VERSION 5.8 ;
BUSBITCHARS "[]" ;
DIVIDERCHAR "/" ;

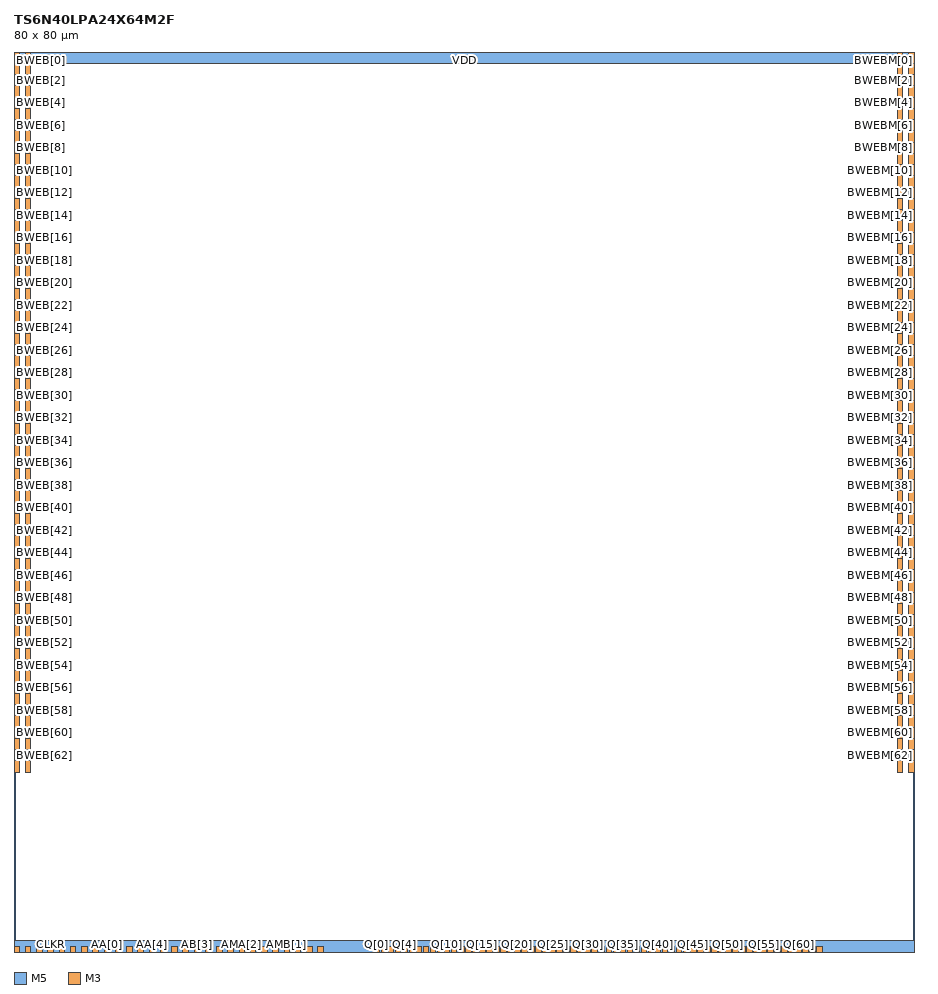
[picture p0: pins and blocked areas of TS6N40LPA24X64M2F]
MACRO TS6N40LPA24X64M2F
  CLASS BLOCK ;
  ORIGIN 0 0 ;
  SIZE 80.0 BY 80.0 ;
  SITE core ;
  SYMMETRY X Y ;

  # ===== Power / Ground =====
  PIN VDD
    DIRECTION INOUT ; USE POWER ;
    PORT
      LAYER M5 ;
        RECT 0.0 79.0 80.0 80.0 ;
    END
  END VDD

  PIN VSS
    DIRECTION INOUT ; USE GROUND ;
    PORT
      LAYER M5 ;
        RECT 0.0 0.0 80.0 1.0 ;
    END
  END VSS

  # ===== Scalars on SOUTH edge (x = 0..32 band) =====
  # order: WEB, CLKW, REB, CLKR, PD, WEBM, REBM, BIST  (step 1.0, width 0.5)
  PIN WEB   DIRECTION INPUT ; USE SIGNAL ;  PORT LAYER M3 ; RECT  0.00 0.00  0.50 0.50 ; END  END WEB
  PIN CLKW  DIRECTION INPUT ; USE SIGNAL ;  PORT LAYER M3 ; RECT  1.00 0.00  1.50 0.50 ; END  END CLKW
  PIN REB   DIRECTION INPUT ; USE SIGNAL ;  PORT LAYER M3 ; RECT  2.00 0.00  2.50 0.50 ; END  END REB
  PIN CLKR  DIRECTION INPUT ; USE SIGNAL ;  PORT LAYER M3 ; RECT  3.00 0.00  3.50 0.50 ; END  END CLKR
  PIN PD    DIRECTION INPUT ; USE SIGNAL ;  PORT LAYER M3 ; RECT  4.00 0.00  4.50 0.50 ; END  END PD
  PIN WEBM  DIRECTION INPUT ; USE SIGNAL ;  PORT LAYER M3 ; RECT  5.00 0.00  5.50 0.50 ; END  END WEBM
  PIN REBM  DIRECTION INPUT ; USE SIGNAL ;  PORT LAYER M3 ; RECT  6.00 0.00  6.50 0.50 ; END  END REBM
  PIN BIST  DIRECTION INPUT ; USE SIGNAL ;  PORT LAYER M3 ; RECT  7.00 0.00  7.50 0.50 ; END  END BIST

  # ===== Address buses (SOUTH, still in x = 0..32 band), step 1.0, width 0.5 =====
  # AA[4:0]
  PIN AA[0] DIRECTION INPUT ; USE SIGNAL ;  PORT LAYER M3 ; RECT  8.00 0.00  8.50 0.50 ; END  END AA[0]
  PIN AA[1] DIRECTION INPUT ; USE SIGNAL ;  PORT LAYER M3 ; RECT  9.00 0.00  9.50 0.50 ; END  END AA[1]
  PIN AA[2] DIRECTION INPUT ; USE SIGNAL ;  PORT LAYER M3 ; RECT 10.00 0.00 10.50 0.50 ; END  END AA[2]
  PIN AA[3] DIRECTION INPUT ; USE SIGNAL ;  PORT LAYER M3 ; RECT 11.00 0.00 11.50 0.50 ; END  END AA[3]
  PIN AA[4] DIRECTION INPUT ; USE SIGNAL ;  PORT LAYER M3 ; RECT 12.00 0.00 12.50 0.50 ; END  END AA[4]

  # AB[4:0]
  PIN AB[0] DIRECTION INPUT ; USE SIGNAL ;  PORT LAYER M3 ; RECT 13.00 0.00 13.50 0.50 ; END  END AB[0]
  PIN AB[1] DIRECTION INPUT ; USE SIGNAL ;  PORT LAYER M3 ; RECT 14.00 0.00 14.50 0.50 ; END  END AB[1]
  PIN AB[2] DIRECTION INPUT ; USE SIGNAL ;  PORT LAYER M3 ; RECT 15.00 0.00 15.50 0.50 ; END  END AB[2]
  PIN AB[3] DIRECTION INPUT ; USE SIGNAL ;  PORT LAYER M3 ; RECT 16.00 0.00 16.50 0.50 ; END  END AB[3]
  PIN AB[4] DIRECTION INPUT ; USE SIGNAL ;  PORT LAYER M3 ; RECT 17.00 0.00 17.50 0.50 ; END  END AB[4]

  # AMA[4:0]
  PIN AMA[0] DIRECTION INPUT ; USE SIGNAL ; PORT LAYER M3 ; RECT 18.00 0.00 18.50 0.50 ; END  END AMA[0]
  PIN AMA[1] DIRECTION INPUT ; USE SIGNAL ; PORT LAYER M3 ; RECT 19.00 0.00 19.50 0.50 ; END  END AMA[1]
  PIN AMA[2] DIRECTION INPUT ; USE SIGNAL ; PORT LAYER M3 ; RECT 20.00 0.00 20.50 0.50 ; END  END AMA[2]
  PIN AMA[3] DIRECTION INPUT ; USE SIGNAL ; PORT LAYER M3 ; RECT 21.00 0.00 21.50 0.50 ; END  END AMA[3]
  PIN AMA[4] DIRECTION INPUT ; USE SIGNAL ; PORT LAYER M3 ; RECT 22.00 0.00 22.50 0.50 ; END  END AMA[4]

  # AMB[4:0]
  PIN AMB[0] DIRECTION INPUT ; USE SIGNAL ; PORT LAYER M3 ; RECT 23.00 0.00 23.50 0.50 ; END  END AMB[0]
  PIN AMB[1] DIRECTION INPUT ; USE SIGNAL ; PORT LAYER M3 ; RECT 24.00 0.00 24.50 0.50 ; END  END AMB[1]
  PIN AMB[2] DIRECTION INPUT ; USE SIGNAL ; PORT LAYER M3 ; RECT 25.00 0.00 25.50 0.50 ; END  END AMB[2]
  PIN AMB[3] DIRECTION INPUT ; USE SIGNAL ; PORT LAYER M3 ; RECT 26.00 0.00 26.50 0.50 ; END  END AMB[3]
  PIN AMB[4] DIRECTION INPUT ; USE SIGNAL ; PORT LAYER M3 ; RECT 27.00 0.00 27.50 0.50 ; END  END AMB[4]

  # (leave x=27..32 empty as a spacer before Q bus)

  # ===== Q[63:0] on SOUTH edge (x = 32..80), step 0.625, width 0.5 =====
  # y = 0.0–0.5
  PIN Q[0]  DIRECTION OUTPUT ; USE SIGNAL ;  PORT LAYER M3 ; RECT 32.000 0.00 32.500 0.50 ; END  END Q[0]
  PIN Q[1]  DIRECTION OUTPUT ; USE SIGNAL ;  PORT LAYER M3 ; RECT 32.625 0.00 33.125 0.50 ; END  END Q[1]
  PIN Q[2]  DIRECTION OUTPUT ; USE SIGNAL ;  PORT LAYER M3 ; RECT 33.250 0.00 33.750 0.50 ; END  END Q[2]
  PIN Q[3]  DIRECTION OUTPUT ; USE SIGNAL ;  PORT LAYER M3 ; RECT 33.875 0.00 34.375 0.50 ; END  END Q[3]
  PIN Q[4]  DIRECTION OUTPUT ; USE SIGNAL ;  PORT LAYER M3 ; RECT 34.500 0.00 35.000 0.50 ; END  END Q[4]
  PIN Q[5]  DIRECTION OUTPUT ; USE SIGNAL ;  PORT LAYER M3 ; RECT 35.125 0.00 35.625 0.50 ; END  END Q[5]
  PIN Q[6]  DIRECTION OUTPUT ; USE SIGNAL ;  PORT LAYER M3 ; RECT 35.750 0.00 36.250 0.50 ; END  END Q[6]
  PIN Q[7]  DIRECTION OUTPUT ; USE SIGNAL ;  PORT LAYER M3 ; RECT 36.375 0.00 36.875 0.50 ; END  END Q[7]
  PIN Q[8]  DIRECTION OUTPUT ; USE SIGNAL ;  PORT LAYER M3 ; RECT 37.000 0.00 37.500 0.50 ; END  END Q[8]
  PIN Q[9]  DIRECTION OUTPUT ; USE SIGNAL ;  PORT LAYER M3 ; RECT 37.625 0.00 38.125 0.50 ; END  END Q[9]
  PIN Q[10] DIRECTION OUTPUT ; USE SIGNAL ;  PORT LAYER M3 ; RECT 38.250 0.00 38.750 0.50 ; END  END Q[10]
  PIN Q[11] DIRECTION OUTPUT ; USE SIGNAL ;  PORT LAYER M3 ; RECT 38.875 0.00 39.375 0.50 ; END  END Q[11]
  PIN Q[12] DIRECTION OUTPUT ; USE SIGNAL ;  PORT LAYER M3 ; RECT 39.500 0.00 40.000 0.50 ; END  END Q[12]
  PIN Q[13] DIRECTION OUTPUT ; USE SIGNAL ;  PORT LAYER M3 ; RECT 40.125 0.00 40.625 0.50 ; END  END Q[13]
  PIN Q[14] DIRECTION OUTPUT ; USE SIGNAL ;  PORT LAYER M3 ; RECT 40.750 0.00 41.250 0.50 ; END  END Q[14]
  PIN Q[15] DIRECTION OUTPUT ; USE SIGNAL ;  PORT LAYER M3 ; RECT 41.375 0.00 41.875 0.50 ; END  END Q[15]
  PIN Q[16] DIRECTION OUTPUT ; USE SIGNAL ;  PORT LAYER M3 ; RECT 42.000 0.00 42.500 0.50 ; END  END Q[16]
  PIN Q[17] DIRECTION OUTPUT ; USE SIGNAL ;  PORT LAYER M3 ; RECT 42.625 0.00 43.125 0.50 ; END  END Q[17]
  PIN Q[18] DIRECTION OUTPUT ; USE SIGNAL ;  PORT LAYER M3 ; RECT 43.250 0.00 43.750 0.50 ; END  END Q[18]
  PIN Q[19] DIRECTION OUTPUT ; USE SIGNAL ;  PORT LAYER M3 ; RECT 43.875 0.00 44.375 0.50 ; END  END Q[19]
  PIN Q[20] DIRECTION OUTPUT ; USE SIGNAL ;  PORT LAYER M3 ; RECT 44.500 0.00 45.000 0.50 ; END  END Q[20]
  PIN Q[21] DIRECTION OUTPUT ; USE SIGNAL ;  PORT LAYER M3 ; RECT 45.125 0.00 45.625 0.50 ; END  END Q[21]
  PIN Q[22] DIRECTION OUTPUT ; USE SIGNAL ;  PORT LAYER M3 ; RECT 45.750 0.00 46.250 0.50 ; END  END Q[22]
  PIN Q[23] DIRECTION OUTPUT ; USE SIGNAL ;  PORT LAYER M3 ; RECT 46.375 0.00 46.875 0.50 ; END  END Q[23]
  PIN Q[24] DIRECTION OUTPUT ; USE SIGNAL ;  PORT LAYER M3 ; RECT 47.000 0.00 47.500 0.50 ; END  END Q[24]
  PIN Q[25] DIRECTION OUTPUT ; USE SIGNAL ;  PORT LAYER M3 ; RECT 47.625 0.00 48.125 0.50 ; END  END Q[25]
  PIN Q[26] DIRECTION OUTPUT ; USE SIGNAL ;  PORT LAYER M3 ; RECT 48.250 0.00 48.750 0.50 ; END  END Q[26]
  PIN Q[27] DIRECTION OUTPUT ; USE SIGNAL ;  PORT LAYER M3 ; RECT 48.875 0.00 49.375 0.50 ; END  END Q[27]
  PIN Q[28] DIRECTION OUTPUT ; USE SIGNAL ;  PORT LAYER M3 ; RECT 49.500 0.00 50.000 0.50 ; END  END Q[28]
  PIN Q[29] DIRECTION OUTPUT ; USE SIGNAL ;  PORT LAYER M3 ; RECT 50.125 0.00 50.625 0.50 ; END  END Q[29]
  PIN Q[30] DIRECTION OUTPUT ; USE SIGNAL ;  PORT LAYER M3 ; RECT 50.750 0.00 51.250 0.50 ; END  END Q[30]
  PIN Q[31] DIRECTION OUTPUT ; USE SIGNAL ;  PORT LAYER M3 ; RECT 51.375 0.00 51.875 0.50 ; END  END Q[31]
  PIN Q[32] DIRECTION OUTPUT ; USE SIGNAL ;  PORT LAYER M3 ; RECT 52.000 0.00 52.500 0.50 ; END  END Q[32]
  PIN Q[33] DIRECTION OUTPUT ; USE SIGNAL ;  PORT LAYER M3 ; RECT 52.625 0.00 53.125 0.50 ; END  END Q[33]
  PIN Q[34] DIRECTION OUTPUT ; USE SIGNAL ;  PORT LAYER M3 ; RECT 53.250 0.00 53.750 0.50 ; END  END Q[34]
  PIN Q[35] DIRECTION OUTPUT ; USE SIGNAL ;  PORT LAYER M3 ; RECT 53.875 0.00 54.375 0.50 ; END  END Q[35]
  PIN Q[36] DIRECTION OUTPUT ; USE SIGNAL ;  PORT LAYER M3 ; RECT 54.500 0.00 55.000 0.50 ; END  END Q[36]
  PIN Q[37] DIRECTION OUTPUT ; USE SIGNAL ;  PORT LAYER M3 ; RECT 55.125 0.00 55.625 0.50 ; END  END Q[37]
  PIN Q[38] DIRECTION OUTPUT ; USE SIGNAL ;  PORT LAYER M3 ; RECT 55.750 0.00 56.250 0.50 ; END  END Q[38]
  PIN Q[39] DIRECTION OUTPUT ; USE SIGNAL ;  PORT LAYER M3 ; RECT 56.375 0.00 56.875 0.50 ; END  END Q[39]
  PIN Q[40] DIRECTION OUTPUT ; USE SIGNAL ;  PORT LAYER M3 ; RECT 57.000 0.00 57.500 0.50 ; END  END Q[40]
  PIN Q[41] DIRECTION OUTPUT ; USE SIGNAL ;  PORT LAYER M3 ; RECT 57.625 0.00 58.125 0.50 ; END  END Q[41]
  PIN Q[42] DIRECTION OUTPUT ; USE SIGNAL ;  PORT LAYER M3 ; RECT 58.250 0.00 58.750 0.50 ; END  END Q[42]
  PIN Q[43] DIRECTION OUTPUT ; USE SIGNAL ;  PORT LAYER M3 ; RECT 58.875 0.00 59.375 0.50 ; END  END Q[43]
  PIN Q[44] DIRECTION OUTPUT ; USE SIGNAL ;  PORT LAYER M3 ; RECT 59.500 0.00 60.000 0.50 ; END  END Q[44]
  PIN Q[45] DIRECTION OUTPUT ; USE SIGNAL ;  PORT LAYER M3 ; RECT 60.125 0.00 60.625 0.50 ; END  END Q[45]
  PIN Q[46] DIRECTION OUTPUT ; USE SIGNAL ;  PORT LAYER M3 ; RECT 60.750 0.00 61.250 0.50 ; END  END Q[46]
  PIN Q[47] DIRECTION OUTPUT ; USE SIGNAL ;  PORT LAYER M3 ; RECT 61.375 0.00 61.875 0.50 ; END  END Q[47]
  PIN Q[48] DIRECTION OUTPUT ; USE SIGNAL ;  PORT LAYER M3 ; RECT 62.000 0.00 62.500 0.50 ; END  END Q[48]
  PIN Q[49] DIRECTION OUTPUT ; USE SIGNAL ;  PORT LAYER M3 ; RECT 62.625 0.00 63.125 0.50 ; END  END Q[49]
  PIN Q[50] DIRECTION OUTPUT ; USE SIGNAL ;  PORT LAYER M3 ; RECT 63.250 0.00 63.750 0.50 ; END  END Q[50]
  PIN Q[51] DIRECTION OUTPUT ; USE SIGNAL ;  PORT LAYER M3 ; RECT 63.875 0.00 64.375 0.50 ; END  END Q[51]
  PIN Q[52] DIRECTION OUTPUT ; USE SIGNAL ;  PORT LAYER M3 ; RECT 64.500 0.00 65.000 0.50 ; END  END Q[52]
  PIN Q[53] DIRECTION OUTPUT ; USE SIGNAL ;  PORT LAYER M3 ; RECT 65.125 0.00 65.625 0.50 ; END  END Q[53]
  PIN Q[54] DIRECTION OUTPUT ; USE SIGNAL ;  PORT LAYER M3 ; RECT 65.750 0.00 66.250 0.50 ; END  END Q[54]
  PIN Q[55] DIRECTION OUTPUT ; USE SIGNAL ;  PORT LAYER M3 ; RECT 66.375 0.00 66.875 0.50 ; END  END Q[55]
  PIN Q[56] DIRECTION OUTPUT ; USE SIGNAL ;  PORT LAYER M3 ; RECT 67.000 0.00 67.500 0.50 ; END  END Q[56]
  PIN Q[57] DIRECTION OUTPUT ; USE SIGNAL ;  PORT LAYER M3 ; RECT 67.625 0.00 68.125 0.50 ; END  END Q[57]
  PIN Q[58] DIRECTION OUTPUT ; USE SIGNAL ;  PORT LAYER M3 ; RECT 68.250 0.00 68.750 0.50 ; END  END Q[58]
  PIN Q[59] DIRECTION OUTPUT ; USE SIGNAL ;  PORT LAYER M3 ; RECT 68.875 0.00 69.375 0.50 ; END  END Q[59]
  PIN Q[60] DIRECTION OUTPUT ; USE SIGNAL ;  PORT LAYER M3 ; RECT 69.500 0.00 70.000 0.50 ; END  END Q[60]
  PIN Q[61] DIRECTION OUTPUT ; USE SIGNAL ;  PORT LAYER M3 ; RECT 70.125 0.00 70.625 0.50 ; END  END Q[61]
  PIN Q[62] DIRECTION OUTPUT ; USE SIGNAL ;  PORT LAYER M3 ; RECT 70.750 0.00 71.250 0.50 ; END  END Q[62]
  PIN Q[63] DIRECTION OUTPUT ; USE SIGNAL ;  PORT LAYER M3 ; RECT 71.375 0.00 71.875 0.50 ; END  END Q[63]

  # ===== D[63:0] on WEST edge (x=0.0–0.5), step 1.0 in Y, top-down from 79 =====
  PIN D[0]  DIRECTION INPUT ; USE SIGNAL ;  PORT LAYER M3 ; RECT 0.00 79.00 0.50 80.00 ; END  END D[0]
  PIN D[1]  DIRECTION INPUT ; USE SIGNAL ;  PORT LAYER M3 ; RECT 0.00 78.00 0.50 79.00 ; END  END D[1]
  PIN D[2]  DIRECTION INPUT ; USE SIGNAL ;  PORT LAYER M3 ; RECT 0.00 77.00 0.50 78.00 ; END  END D[2]
  PIN D[3]  DIRECTION INPUT ; USE SIGNAL ;  PORT LAYER M3 ; RECT 0.00 76.00 0.50 77.00 ; END  END D[3]
  PIN D[4]  DIRECTION INPUT ; USE SIGNAL ;  PORT LAYER M3 ; RECT 0.00 75.00 0.50 76.00 ; END  END D[4]
  PIN D[5]  DIRECTION INPUT ; USE SIGNAL ;  PORT LAYER M3 ; RECT 0.00 74.00 0.50 75.00 ; END  END D[5]
  PIN D[6]  DIRECTION INPUT ; USE SIGNAL ;  PORT LAYER M3 ; RECT 0.00 73.00 0.50 74.00 ; END  END D[6]
  PIN D[7]  DIRECTION INPUT ; USE SIGNAL ;  PORT LAYER M3 ; RECT 0.00 72.00 0.50 73.00 ; END  END D[7]
  PIN D[8]  DIRECTION INPUT ; USE SIGNAL ;  PORT LAYER M3 ; RECT 0.00 71.00 0.50 72.00 ; END  END D[8]
  PIN D[9]  DIRECTION INPUT ; USE SIGNAL ;  PORT LAYER M3 ; RECT 0.00 70.00 0.50 71.00 ; END  END D[9]
  PIN D[10] DIRECTION INPUT ; USE SIGNAL ;  PORT LAYER M3 ; RECT 0.00 69.00 0.50 70.00 ; END  END D[10]
  PIN D[11] DIRECTION INPUT ; USE SIGNAL ;  PORT LAYER M3 ; RECT 0.00 68.00 0.50 69.00 ; END  END D[11]
  PIN D[12] DIRECTION INPUT ; USE SIGNAL ;  PORT LAYER M3 ; RECT 0.00 67.00 0.50 68.00 ; END  END D[12]
  PIN D[13] DIRECTION INPUT ; USE SIGNAL ;  PORT LAYER M3 ; RECT 0.00 66.00 0.50 67.00 ; END  END D[13]
  PIN D[14] DIRECTION INPUT ; USE SIGNAL ;  PORT LAYER M3 ; RECT 0.00 65.00 0.50 66.00 ; END  END D[14]
  PIN D[15] DIRECTION INPUT ; USE SIGNAL ;  PORT LAYER M3 ; RECT 0.00 64.00 0.50 65.00 ; END  END D[15]
  PIN D[16] DIRECTION INPUT ; USE SIGNAL ;  PORT LAYER M3 ; RECT 0.00 63.00 0.50 64.00 ; END  END D[16]
  PIN D[17] DIRECTION INPUT ; USE SIGNAL ;  PORT LAYER M3 ; RECT 0.00 62.00 0.50 63.00 ; END  END D[17]
  PIN D[18] DIRECTION INPUT ; USE SIGNAL ;  PORT LAYER M3 ; RECT 0.00 61.00 0.50 62.00 ; END  END D[18]
  PIN D[19] DIRECTION INPUT ; USE SIGNAL ;  PORT LAYER M3 ; RECT 0.00 60.00 0.50 61.00 ; END  END D[19]
  PIN D[20] DIRECTION INPUT ; USE SIGNAL ;  PORT LAYER M3 ; RECT 0.00 59.00 0.50 60.00 ; END  END D[20]
  PIN D[21] DIRECTION INPUT ; USE SIGNAL ;  PORT LAYER M3 ; RECT 0.00 58.00 0.50 59.00 ; END  END D[21]
  PIN D[22] DIRECTION INPUT ; USE SIGNAL ;  PORT LAYER M3 ; RECT 0.00 57.00 0.50 58.00 ; END  END D[22]
  PIN D[23] DIRECTION INPUT ; USE SIGNAL ;  PORT LAYER M3 ; RECT 0.00 56.00 0.50 57.00 ; END  END D[23]
  PIN D[24] DIRECTION INPUT ; USE SIGNAL ;  PORT LAYER M3 ; RECT 0.00 55.00 0.50 56.00 ; END  END D[24]
  PIN D[25] DIRECTION INPUT ; USE SIGNAL ;  PORT LAYER M3 ; RECT 0.00 54.00 0.50 55.00 ; END  END D[25]
  PIN D[26] DIRECTION INPUT ; USE SIGNAL ;  PORT LAYER M3 ; RECT 0.00 53.00 0.50 54.00 ; END  END D[26]
  PIN D[27] DIRECTION INPUT ; USE SIGNAL ;  PORT LAYER M3 ; RECT 0.00 52.00 0.50 53.00 ; END  END D[27]
  PIN D[28] DIRECTION INPUT ; USE SIGNAL ;  PORT LAYER M3 ; RECT 0.00 51.00 0.50 52.00 ; END  END D[28]
  PIN D[29] DIRECTION INPUT ; USE SIGNAL ;  PORT LAYER M3 ; RECT 0.00 50.00 0.50 51.00 ; END  END D[29]
  PIN D[30] DIRECTION INPUT ; USE SIGNAL ;  PORT LAYER M3 ; RECT 0.00 49.00 0.50 50.00 ; END  END D[30]
  PIN D[31] DIRECTION INPUT ; USE SIGNAL ;  PORT LAYER M3 ; RECT 0.00 48.00 0.50 49.00 ; END  END D[31]
  PIN D[32] DIRECTION INPUT ; USE SIGNAL ;  PORT LAYER M3 ; RECT 0.00 47.00 0.50 48.00 ; END  END D[32]
  PIN D[33] DIRECTION INPUT ; USE SIGNAL ;  PORT LAYER M3 ; RECT 0.00 46.00 0.50 47.00 ; END  END D[33]
  PIN D[34] DIRECTION INPUT ; USE SIGNAL ;  PORT LAYER M3 ; RECT 0.00 45.00 0.50 46.00 ; END  END D[34]
  PIN D[35] DIRECTION INPUT ; USE SIGNAL ;  PORT LAYER M3 ; RECT 0.00 44.00 0.50 45.00 ; END  END D[35]
  PIN D[36] DIRECTION INPUT ; USE SIGNAL ;  PORT LAYER M3 ; RECT 0.00 43.00 0.50 44.00 ; END  END D[36]
  PIN D[37] DIRECTION INPUT ; USE SIGNAL ;  PORT LAYER M3 ; RECT 0.00 42.00 0.50 43.00 ; END  END D[37]
  PIN D[38] DIRECTION INPUT ; USE SIGNAL ;  PORT LAYER M3 ; RECT 0.00 41.00 0.50 42.00 ; END  END D[38]
  PIN D[39] DIRECTION INPUT ; USE SIGNAL ;  PORT LAYER M3 ; RECT 0.00 40.00 0.50 41.00 ; END  END D[39]
  PIN D[40] DIRECTION INPUT ; USE SIGNAL ;  PORT LAYER M3 ; RECT 0.00 39.00 0.50 40.00 ; END  END D[40]
  PIN D[41] DIRECTION INPUT ; USE SIGNAL ;  PORT LAYER M3 ; RECT 0.00 38.00 0.50 39.00 ; END  END D[41]
  PIN D[42] DIRECTION INPUT ; USE SIGNAL ;  PORT LAYER M3 ; RECT 0.00 37.00 0.50 38.00 ; END  END D[42]
  PIN D[43] DIRECTION INPUT ; USE SIGNAL ;  PORT LAYER M3 ; RECT 0.00 36.00 0.50 37.00 ; END  END D[43]
  PIN D[44] DIRECTION INPUT ; USE SIGNAL ;  PORT LAYER M3 ; RECT 0.00 35.00 0.50 36.00 ; END  END D[44]
  PIN D[45] DIRECTION INPUT ; USE SIGNAL ;  PORT LAYER M3 ; RECT 0.00 34.00 0.50 35.00 ; END  END D[45]
  PIN D[46] DIRECTION INPUT ; USE SIGNAL ;  PORT LAYER M3 ; RECT 0.00 33.00 0.50 34.00 ; END  END D[46]
  PIN D[47] DIRECTION INPUT ; USE SIGNAL ;  PORT LAYER M3 ; RECT 0.00 32.00 0.50 33.00 ; END  END D[47]
  PIN D[48] DIRECTION INPUT ; USE SIGNAL ;  PORT LAYER M3 ; RECT 0.00 31.00 0.50 32.00 ; END  END D[48]
  PIN D[49] DIRECTION INPUT ; USE SIGNAL ;  PORT LAYER M3 ; RECT 0.00 30.00 0.50 31.00 ; END  END D[49]
  PIN D[50] DIRECTION INPUT ; USE SIGNAL ;  PORT LAYER M3 ; RECT 0.00 29.00 0.50 30.00 ; END  END D[50]
  PIN D[51] DIRECTION INPUT ; USE SIGNAL ;  PORT LAYER M3 ; RECT 0.00 28.00 0.50 29.00 ; END  END D[51]
  PIN D[52] DIRECTION INPUT ; USE SIGNAL ;  PORT LAYER M3 ; RECT 0.00 27.00 0.50 28.00 ; END  END D[52]
  PIN D[53] DIRECTION INPUT ; USE SIGNAL ;  PORT LAYER M3 ; RECT 0.00 26.00 0.50 27.00 ; END  END D[53]
  PIN D[54] DIRECTION INPUT ; USE SIGNAL ;  PORT LAYER M3 ; RECT 0.00 25.00 0.50 26.00 ; END  END D[54]
  PIN D[55] DIRECTION INPUT ; USE SIGNAL ;  PORT LAYER M3 ; RECT 0.00 24.00 0.50 25.00 ; END  END D[55]
  PIN D[56] DIRECTION INPUT ; USE SIGNAL ;  PORT LAYER M3 ; RECT 0.00 23.00 0.50 24.00 ; END  END D[56]
  PIN D[57] DIRECTION INPUT ; USE SIGNAL ;  PORT LAYER M3 ; RECT 0.00 22.00 0.50 23.00 ; END  END D[57]
  PIN D[58] DIRECTION INPUT ; USE SIGNAL ;  PORT LAYER M3 ; RECT 0.00 21.00 0.50 22.00 ; END  END D[58]
  PIN D[59] DIRECTION INPUT ; USE SIGNAL ;  PORT LAYER M3 ; RECT 0.00 20.00 0.50 21.00 ; END  END D[59]
  PIN D[60] DIRECTION INPUT ; USE SIGNAL ;  PORT LAYER M3 ; RECT 0.00 19.00 0.50 20.00 ; END  END D[60]
  PIN D[61] DIRECTION INPUT ; USE SIGNAL ;  PORT LAYER M3 ; RECT 0.00 18.00 0.50 19.00 ; END  END D[61]
  PIN D[62] DIRECTION INPUT ; USE SIGNAL ;  PORT LAYER M3 ; RECT 0.00 17.00 0.50 18.00 ; END  END D[62]
  PIN D[63] DIRECTION INPUT ; USE SIGNAL ;  PORT LAYER M3 ; RECT 0.00 16.00 0.50 17.00 ; END  END D[63]

  # ===== DM[63:0] on EAST edge (x=79.5–80.0), step 1.0 in Y, top-down from 79 =====
  PIN DM[0]  DIRECTION INPUT ; USE SIGNAL ; PORT LAYER M3 ; RECT 79.50 79.00 80.00 80.00 ; END  END DM[0]
  PIN DM[1]  DIRECTION INPUT ; USE SIGNAL ; PORT LAYER M3 ; RECT 79.50 78.00 80.00 79.00 ; END  END DM[1]
  PIN DM[2]  DIRECTION INPUT ; USE SIGNAL ; PORT LAYER M3 ; RECT 79.50 77.00 80.00 78.00 ; END  END DM[2]
  PIN DM[3]  DIRECTION INPUT ; USE SIGNAL ; PORT LAYER M3 ; RECT 79.50 76.00 80.00 77.00 ; END  END DM[3]
  PIN DM[4]  DIRECTION INPUT ; USE SIGNAL ; PORT LAYER M3 ; RECT 79.50 75.00 80.00 76.00 ; END  END DM[4]
  PIN DM[5]  DIRECTION INPUT ; USE SIGNAL ; PORT LAYER M3 ; RECT 79.50 74.00 80.00 75.00 ; END  END DM[5]
  PIN DM[6]  DIRECTION INPUT ; USE SIGNAL ; PORT LAYER M3 ; RECT 79.50 73.00 80.00 74.00 ; END  END DM[6]
  PIN DM[7]  DIRECTION INPUT ; USE SIGNAL ; PORT LAYER M3 ; RECT 79.50 72.00 80.00 73.00 ; END  END DM[7]
  PIN DM[8]  DIRECTION INPUT ; USE SIGNAL ; PORT LAYER M3 ; RECT 79.50 71.00 80.00 72.00 ; END  END DM[8]
  PIN DM[9]  DIRECTION INPUT ; USE SIGNAL ; PORT LAYER M3 ; RECT 79.50 70.00 80.00 71.00 ; END  END DM[9]
  PIN DM[10] DIRECTION INPUT ; USE SIGNAL ; PORT LAYER M3 ; RECT 79.50 69.00 80.00 70.00 ; END  END DM[10]
  PIN DM[11] DIRECTION INPUT ; USE SIGNAL ; PORT LAYER M3 ; RECT 79.50 68.00 80.00 69.00 ; END  END DM[11]
  PIN DM[12] DIRECTION INPUT ; USE SIGNAL ; PORT LAYER M3 ; RECT 79.50 67.00 80.00 68.00 ; END  END DM[12]
  PIN DM[13] DIRECTION INPUT ; USE SIGNAL ; PORT LAYER M3 ; RECT 79.50 66.00 80.00 67.00 ; END  END DM[13]
  PIN DM[14] DIRECTION INPUT ; USE SIGNAL ; PORT LAYER M3 ; RECT 79.50 65.00 80.00 66.00 ; END  END DM[14]
  PIN DM[15] DIRECTION INPUT ; USE SIGNAL ; PORT LAYER M3 ; RECT 79.50 64.00 80.00 65.00 ; END  END DM[15]
  PIN DM[16] DIRECTION INPUT ; USE SIGNAL ; PORT LAYER M3 ; RECT 79.50 63.00 80.00 64.00 ; END  END DM[16]
  PIN DM[17] DIRECTION INPUT ; USE SIGNAL ; PORT LAYER M3 ; RECT 79.50 62.00 80.00 63.00 ; END  END DM[17]
  PIN DM[18] DIRECTION INPUT ; USE SIGNAL ; PORT LAYER M3 ; RECT 79.50 61.00 80.00 62.00 ; END  END DM[18]
  PIN DM[19] DIRECTION INPUT ; USE SIGNAL ; PORT LAYER M3 ; RECT 79.50 60.00 80.00 61.00 ; END  END DM[19]
  PIN DM[20] DIRECTION INPUT ; USE SIGNAL ; PORT LAYER M3 ; RECT 79.50 59.00 80.00 60.00 ; END  END DM[20]
  PIN DM[21] DIRECTION INPUT ; USE SIGNAL ; PORT LAYER M3 ; RECT 79.50 58.00 80.00 59.00 ; END  END DM[21]
  PIN DM[22] DIRECTION INPUT ; USE SIGNAL ; PORT LAYER M3 ; RECT 79.50 57.00 80.00 58.00 ; END  END DM[22]
  PIN DM[23] DIRECTION INPUT ; USE SIGNAL ; PORT LAYER M3 ; RECT 79.50 56.00 80.00 57.00 ; END  END DM[23]
  PIN DM[24] DIRECTION INPUT ; USE SIGNAL ; PORT LAYER M3 ; RECT 79.50 55.00 80.00 56.00 ; END  END DM[24]
  PIN DM[25] DIRECTION INPUT ; USE SIGNAL ; PORT LAYER M3 ; RECT 79.50 54.00 80.00 55.00 ; END  END DM[25]
  PIN DM[26] DIRECTION INPUT ; USE SIGNAL ; PORT LAYER M3 ; RECT 79.50 53.00 80.00 54.00 ; END  END DM[26]
  PIN DM[27] DIRECTION INPUT ; USE SIGNAL ; PORT LAYER M3 ; RECT 79.50 52.00 80.00 53.00 ; END  END DM[27]
  PIN DM[28] DIRECTION INPUT ; USE SIGNAL ; PORT LAYER M3 ; RECT 79.50 51.00 80.00 52.00 ; END  END DM[28]
  PIN DM[29] DIRECTION INPUT ; USE SIGNAL ; PORT LAYER M3 ; RECT 79.50 50.00 80.00 51.00 ; END  END DM[29]
  PIN DM[30] DIRECTION INPUT ; USE SIGNAL ; PORT LAYER M3 ; RECT 79.50 49.00 80.00 50.00 ; END  END DM[30]
  PIN DM[31] DIRECTION INPUT ; USE SIGNAL ; PORT LAYER M3 ; RECT 79.50 48.00 80.00 49.00 ; END  END DM[31]
  PIN DM[32] DIRECTION INPUT ; USE SIGNAL ; PORT LAYER M3 ; RECT 79.50 47.00 80.00 48.00 ; END  END DM[32]
  PIN DM[33] DIRECTION INPUT ; USE SIGNAL ; PORT LAYER M3 ; RECT 79.50 46.00 80.00 47.00 ; END  END DM[33]
  PIN DM[34] DIRECTION INPUT ; USE SIGNAL ; PORT LAYER M3 ; RECT 79.50 45.00 80.00 46.00 ; END  END DM[34]
  PIN DM[35] DIRECTION INPUT ; USE SIGNAL ; PORT LAYER M3 ; RECT 79.50 44.00 80.00 45.00 ; END  END DM[35]
  PIN DM[36] DIRECTION INPUT ; USE SIGNAL ; PORT LAYER M3 ; RECT 79.50 43.00 80.00 44.00 ; END  END DM[36]
  PIN DM[37] DIRECTION INPUT ; USE SIGNAL ; PORT LAYER M3 ; RECT 79.50 42.00 80.00 43.00 ; END  END DM[37]
  PIN DM[38] DIRECTION INPUT ; USE SIGNAL ; PORT LAYER M3 ; RECT 79.50 41.00 80.00 42.00 ; END  END DM[38]
  PIN DM[39] DIRECTION INPUT ; USE SIGNAL ; PORT LAYER M3 ; RECT 79.50 40.00 80.00 41.00 ; END  END DM[39]
  PIN DM[40] DIRECTION INPUT ; USE SIGNAL ; PORT LAYER M3 ; RECT 79.50 39.00 80.00 40.00 ; END  END DM[40]
  PIN DM[41] DIRECTION INPUT ; USE SIGNAL ; PORT LAYER M3 ; RECT 79.50 38.00 80.00 39.00 ; END  END DM[41]
  PIN DM[42] DIRECTION INPUT ; USE SIGNAL ; PORT LAYER M3 ; RECT 79.50 37.00 80.00 38.00 ; END  END DM[42]
  PIN DM[43] DIRECTION INPUT ; USE SIGNAL ; PORT LAYER M3 ; RECT 79.50 36.00 80.00 37.00 ; END  END DM[43]
  PIN DM[44] DIRECTION INPUT ; USE SIGNAL ; PORT LAYER M3 ; RECT 79.50 35.00 80.00 36.00 ; END  END DM[44]
  PIN DM[45] DIRECTION INPUT ; USE SIGNAL ; PORT LAYER M3 ; RECT 79.50 34.00 80.00 35.00 ; END  END DM[45]
  PIN DM[46] DIRECTION INPUT ; USE SIGNAL ; PORT LAYER M3 ; RECT 79.50 33.00 80.00 34.00 ; END  END DM[46]
  PIN DM[47] DIRECTION INPUT ; USE SIGNAL ; PORT LAYER M3 ; RECT 79.50 32.00 80.00 33.00 ; END  END DM[47]
  PIN DM[48] DIRECTION INPUT ; USE SIGNAL ; PORT LAYER M3 ; RECT 79.50 31.00 80.00 32.00 ; END  END DM[48]
  PIN DM[49] DIRECTION INPUT ; USE SIGNAL ; PORT LAYER M3 ; RECT 79.50 30.00 80.00 31.00 ; END  END DM[49]
  PIN DM[50] DIRECTION INPUT ; USE SIGNAL ; PORT LAYER M3 ; RECT 79.50 29.00 80.00 30.00 ; END  END DM[50]
  PIN DM[51] DIRECTION INPUT ; USE SIGNAL ; PORT LAYER M3 ; RECT 79.50 28.00 80.00 29.00 ; END  END DM[51]
  PIN DM[52] DIRECTION INPUT ; USE SIGNAL ; PORT LAYER M3 ; RECT 79.50 27.00 80.00 28.00 ; END  END DM[52]
  PIN DM[53] DIRECTION INPUT ; USE SIGNAL ; PORT LAYER M3 ; RECT 79.50 26.00 80.00 27.00 ; END  END DM[53]
  PIN DM[54] DIRECTION INPUT ; USE SIGNAL ; PORT LAYER M3 ; RECT 79.50 25.00 80.00 26.00 ; END  END DM[54]
  PIN DM[55] DIRECTION INPUT ; USE SIGNAL ; PORT LAYER M3 ; RECT 79.50 24.00 80.00 25.00 ; END  END DM[55]
  PIN DM[56] DIRECTION INPUT ; USE SIGNAL ; PORT LAYER M3 ; RECT 79.50 23.00 80.00 24.00 ; END  END DM[56]
  PIN DM[57] DIRECTION INPUT ; USE SIGNAL ; PORT LAYER M3 ; RECT 79.50 22.00 80.00 23.00 ; END  END DM[57]
  PIN DM[58] DIRECTION INPUT ; USE SIGNAL ; PORT LAYER M3 ; RECT 79.50 21.00 80.00 22.00 ; END  END DM[58]
  PIN DM[59] DIRECTION INPUT ; USE SIGNAL ; PORT LAYER M3 ; RECT 79.50 20.00 80.00 21.00 ; END  END DM[59]
  PIN DM[60] DIRECTION INPUT ; USE SIGNAL ; PORT LAYER M3 ; RECT 79.50 19.00 80.00 20.00 ; END  END DM[60]
  PIN DM[61] DIRECTION INPUT ; USE SIGNAL ; PORT LAYER M3 ; RECT 79.50 18.00 80.00 19.00 ; END  END DM[61]
  PIN DM[62] DIRECTION INPUT ; USE SIGNAL ; PORT LAYER M3 ; RECT 79.50 17.00 80.00 18.00 ; END  END DM[62]
  PIN DM[63] DIRECTION INPUT ; USE SIGNAL ; PORT LAYER M3 ; RECT 79.50 16.00 80.00 17.00 ; END  END DM[63]
# =========================
# BWEB[63:0]
# =========================
PIN BWEB[0]
  DIRECTION INPUT ; USE SIGNAL ;
  PORT
    LAYER M3 ;
      RECT  1.00 79.00  1.50 80.00 ;
  END
END BWEB[0]

PIN BWEB[1]
  DIRECTION INPUT ; USE SIGNAL ;
  PORT
    LAYER M3 ;
      RECT  1.00 78.00  1.50 79.00 ;
  END
END BWEB[1]

PIN BWEB[2]
  DIRECTION INPUT ; USE SIGNAL ;
  PORT
    LAYER M3 ;
      RECT  1.00 77.00  1.50 78.00 ;
  END
END BWEB[2]

PIN BWEB[3]
  DIRECTION INPUT ; USE SIGNAL ;
  PORT
    LAYER M3 ;
      RECT  1.00 76.00  1.50 77.00 ;
  END
END BWEB[3]

PIN BWEB[4]
  DIRECTION INPUT ; USE SIGNAL ;
  PORT
    LAYER M3 ;
      RECT  1.00 75.00  1.50 76.00 ;
  END
END BWEB[4]

PIN BWEB[5]
  DIRECTION INPUT ; USE SIGNAL ;
  PORT
    LAYER M3 ;
      RECT  1.00 74.00  1.50 75.00 ;
  END
END BWEB[5]

PIN BWEB[6]
  DIRECTION INPUT ; USE SIGNAL ;
  PORT
    LAYER M3 ;
      RECT  1.00 73.00  1.50 74.00 ;
  END
END BWEB[6]

PIN BWEB[7]
  DIRECTION INPUT ; USE SIGNAL ;
  PORT
    LAYER M3 ;
      RECT  1.00 72.00  1.50 73.00 ;
  END
END BWEB[7]

PIN BWEB[8]
  DIRECTION INPUT ; USE SIGNAL ;
  PORT
    LAYER M3 ;
      RECT  1.00 71.00  1.50 72.00 ;
  END
END BWEB[8]

PIN BWEB[9]
  DIRECTION INPUT ; USE SIGNAL ;
  PORT
    LAYER M3 ;
      RECT  1.00 70.00  1.50 71.00 ;
  END
END BWEB[9]

PIN BWEB[10]
  DIRECTION INPUT ; USE SIGNAL ;
  PORT
    LAYER M3 ;
      RECT  1.00 69.00  1.50 70.00 ;
  END
END BWEB[10]

PIN BWEB[11]
  DIRECTION INPUT ; USE SIGNAL ;
  PORT
    LAYER M3 ;
      RECT  1.00 68.00  1.50 69.00 ;
  END
END BWEB[11]

PIN BWEB[12]
  DIRECTION INPUT ; USE SIGNAL ;
  PORT
    LAYER M3 ;
      RECT  1.00 67.00  1.50 68.00 ;
  END
END BWEB[12]

PIN BWEB[13]
  DIRECTION INPUT ; USE SIGNAL ;
  PORT
    LAYER M3 ;
      RECT  1.00 66.00  1.50 67.00 ;
  END
END BWEB[13]

PIN BWEB[14]
  DIRECTION INPUT ; USE SIGNAL ;
  PORT
    LAYER M3 ;
      RECT  1.00 65.00  1.50 66.00 ;
  END
END BWEB[14]

PIN BWEB[15]
  DIRECTION INPUT ; USE SIGNAL ;
  PORT
    LAYER M3 ;
      RECT  1.00 64.00  1.50 65.00 ;
  END
END BWEB[15]

PIN BWEB[16]
  DIRECTION INPUT ; USE SIGNAL ;
  PORT
    LAYER M3 ;
      RECT  1.00 63.00  1.50 64.00 ;
  END
END BWEB[16]

PIN BWEB[17]
  DIRECTION INPUT ; USE SIGNAL ;
  PORT
    LAYER M3 ;
      RECT  1.00 62.00  1.50 63.00 ;
  END
END BWEB[17]

PIN BWEB[18]
  DIRECTION INPUT ; USE SIGNAL ;
  PORT
    LAYER M3 ;
      RECT  1.00 61.00  1.50 62.00 ;
  END
END BWEB[18]

PIN BWEB[19]
  DIRECTION INPUT ; USE SIGNAL ;
  PORT
    LAYER M3 ;
      RECT  1.00 60.00  1.50 61.00 ;
  END
END BWEB[19]

PIN BWEB[20]
  DIRECTION INPUT ; USE SIGNAL ;
  PORT
    LAYER M3 ;
      RECT  1.00 59.00  1.50 60.00 ;
  END
END BWEB[20]

PIN BWEB[21]
  DIRECTION INPUT ; USE SIGNAL ;
  PORT
    LAYER M3 ;
      RECT  1.00 58.00  1.50 59.00 ;
  END
END BWEB[21]

PIN BWEB[22]
  DIRECTION INPUT ; USE SIGNAL ;
  PORT
    LAYER M3 ;
      RECT  1.00 57.00  1.50 58.00 ;
  END
END BWEB[22]

PIN BWEB[23]
  DIRECTION INPUT ; USE SIGNAL ;
  PORT
    LAYER M3 ;
      RECT  1.00 56.00  1.50 57.00 ;
  END
END BWEB[23]

PIN BWEB[24]
  DIRECTION INPUT ; USE SIGNAL ;
  PORT
    LAYER M3 ;
      RECT  1.00 55.00  1.50 56.00 ;
  END
END BWEB[24]

PIN BWEB[25]
  DIRECTION INPUT ; USE SIGNAL ;
  PORT
    LAYER M3 ;
      RECT  1.00 54.00  1.50 55.00 ;
  END
END BWEB[25]

PIN BWEB[26]
  DIRECTION INPUT ; USE SIGNAL ;
  PORT
    LAYER M3 ;
      RECT  1.00 53.00  1.50 54.00 ;
  END
END BWEB[26]

PIN BWEB[27]
  DIRECTION INPUT ; USE SIGNAL ;
  PORT
    LAYER M3 ;
      RECT  1.00 52.00  1.50 53.00 ;
  END
END BWEB[27]

PIN BWEB[28]
  DIRECTION INPUT ; USE SIGNAL ;
  PORT
    LAYER M3 ;
      RECT  1.00 51.00  1.50 52.00 ;
  END
END BWEB[28]

PIN BWEB[29]
  DIRECTION INPUT ; USE SIGNAL ;
  PORT
    LAYER M3 ;
      RECT  1.00 50.00  1.50 51.00 ;
  END
END BWEB[29]

PIN BWEB[30]
  DIRECTION INPUT ; USE SIGNAL ;
  PORT
    LAYER M3 ;
      RECT  1.00 49.00  1.50 50.00 ;
  END
END BWEB[30]

PIN BWEB[31]
  DIRECTION INPUT ; USE SIGNAL ;
  PORT
    LAYER M3 ;
      RECT  1.00 48.00  1.50 49.00 ;
  END
END BWEB[31]

PIN BWEB[32]
  DIRECTION INPUT ; USE SIGNAL ;
  PORT
    LAYER M3 ;
      RECT  1.00 47.00  1.50 48.00 ;
  END
END BWEB[32]

PIN BWEB[33]
  DIRECTION INPUT ; USE SIGNAL ;
  PORT
    LAYER M3 ;
      RECT  1.00 46.00  1.50 47.00 ;
  END
END BWEB[33]

PIN BWEB[34]
  DIRECTION INPUT ; USE SIGNAL ;
  PORT
    LAYER M3 ;
      RECT  1.00 45.00  1.50 46.00 ;
  END
END BWEB[34]

PIN BWEB[35]
  DIRECTION INPUT ; USE SIGNAL ;
  PORT
    LAYER M3 ;
      RECT  1.00 44.00  1.50 45.00 ;
  END
END BWEB[35]

PIN BWEB[36]
  DIRECTION INPUT ; USE SIGNAL ;
  PORT
    LAYER M3 ;
      RECT  1.00 43.00  1.50 44.00 ;
  END
END BWEB[36]

PIN BWEB[37]
  DIRECTION INPUT ; USE SIGNAL ;
  PORT
    LAYER M3 ;
      RECT  1.00 42.00  1.50 43.00 ;
  END
END BWEB[37]

PIN BWEB[38]
  DIRECTION INPUT ; USE SIGNAL ;
  PORT
    LAYER M3 ;
      RECT  1.00 41.00  1.50 42.00 ;
  END
END BWEB[38]

PIN BWEB[39]
  DIRECTION INPUT ; USE SIGNAL ;
  PORT
    LAYER M3 ;
      RECT  1.00 40.00  1.50 41.00 ;
  END
END BWEB[39]

PIN BWEB[40]
  DIRECTION INPUT ; USE SIGNAL ;
  PORT
    LAYER M3 ;
      RECT  1.00 39.00  1.50 40.00 ;
  END
END BWEB[40]

PIN BWEB[41]
  DIRECTION INPUT ; USE SIGNAL ;
  PORT
    LAYER M3 ;
      RECT  1.00 38.00  1.50 39.00 ;
  END
END BWEB[41]

PIN BWEB[42]
  DIRECTION INPUT ; USE SIGNAL ;
  PORT
    LAYER M3 ;
      RECT  1.00 37.00  1.50 38.00 ;
  END
END BWEB[42]

PIN BWEB[43]
  DIRECTION INPUT ; USE SIGNAL ;
  PORT
    LAYER M3 ;
      RECT  1.00 36.00  1.50 37.00 ;
  END
END BWEB[43]

PIN BWEB[44]
  DIRECTION INPUT ; USE SIGNAL ;
  PORT
    LAYER M3 ;
      RECT  1.00 35.00  1.50 36.00 ;
  END
END BWEB[44]

PIN BWEB[45]
  DIRECTION INPUT ; USE SIGNAL ;
  PORT
    LAYER M3 ;
      RECT  1.00 34.00  1.50 35.00 ;
  END
END BWEB[45]

PIN BWEB[46]
  DIRECTION INPUT ; USE SIGNAL ;
  PORT
    LAYER M3 ;
      RECT  1.00 33.00  1.50 34.00 ;
  END
END BWEB[46]

PIN BWEB[47]
  DIRECTION INPUT ; USE SIGNAL ;
  PORT
    LAYER M3 ;
      RECT  1.00 32.00  1.50 33.00 ;
  END
END BWEB[47]

PIN BWEB[48]
  DIRECTION INPUT ; USE SIGNAL ;
  PORT
    LAYER M3 ;
      RECT  1.00 31.00  1.50 32.00 ;
  END
END BWEB[48]

PIN BWEB[49]
  DIRECTION INPUT ; USE SIGNAL ;
  PORT
    LAYER M3 ;
      RECT  1.00 30.00  1.50 31.00 ;
  END
END BWEB[49]

PIN BWEB[50]
  DIRECTION INPUT ; USE SIGNAL ;
  PORT
    LAYER M3 ;
      RECT  1.00 29.00  1.50 30.00 ;
  END
END BWEB[50]

PIN BWEB[51]
  DIRECTION INPUT ; USE SIGNAL ;
  PORT
    LAYER M3 ;
      RECT  1.00 28.00  1.50 29.00 ;
  END
END BWEB[51]

PIN BWEB[52]
  DIRECTION INPUT ; USE SIGNAL ;
  PORT
    LAYER M3 ;
      RECT  1.00 27.00  1.50 28.00 ;
  END
END BWEB[52]

PIN BWEB[53]
  DIRECTION INPUT ; USE SIGNAL ;
  PORT
    LAYER M3 ;
      RECT  1.00 26.00  1.50 27.00 ;
  END
END BWEB[53]

PIN BWEB[54]
  DIRECTION INPUT ; USE SIGNAL ;
  PORT
    LAYER M3 ;
      RECT  1.00 25.00  1.50 26.00 ;
  END
END BWEB[54]

PIN BWEB[55]
  DIRECTION INPUT ; USE SIGNAL ;
  PORT
    LAYER M3 ;
      RECT  1.00 24.00  1.50 25.00 ;
  END
END BWEB[55]

PIN BWEB[56]
  DIRECTION INPUT ; USE SIGNAL ;
  PORT
    LAYER M3 ;
      RECT  1.00 23.00  1.50 24.00 ;
  END
END BWEB[56]

PIN BWEB[57]
  DIRECTION INPUT ; USE SIGNAL ;
  PORT
    LAYER M3 ;
      RECT  1.00 22.00  1.50 23.00 ;
  END
END BWEB[57]

PIN BWEB[58]
  DIRECTION INPUT ; USE SIGNAL ;
  PORT
    LAYER M3 ;
      RECT  1.00 21.00  1.50 22.00 ;
  END
END BWEB[58]

PIN BWEB[59]
  DIRECTION INPUT ; USE SIGNAL ;
  PORT
    LAYER M3 ;
      RECT  1.00 20.00  1.50 21.00 ;
  END
END BWEB[59]

PIN BWEB[60]
  DIRECTION INPUT ; USE SIGNAL ;
  PORT
    LAYER M3 ;
      RECT  1.00 19.00  1.50 20.00 ;
  END
END BWEB[60]

PIN BWEB[61]
  DIRECTION INPUT ; USE SIGNAL ;
  PORT
    LAYER M3 ;
      RECT  1.00 18.00  1.50 19.00 ;
  END
END BWEB[61]

PIN BWEB[62]
  DIRECTION INPUT ; USE SIGNAL ;
  PORT
    LAYER M3 ;
      RECT  1.00 17.00  1.50 18.00 ;
  END
END BWEB[62]

PIN BWEB[63]
  DIRECTION INPUT ; USE SIGNAL ;
  PORT
    LAYER M3 ;
      RECT  1.00 16.00  1.50 17.00 ;
  END
END BWEB[63]

# =========================
# BWEBM[63:0]
# =========================
PIN BWEBM[0]
  DIRECTION INPUT ; USE SIGNAL ;
  PORT
    LAYER M3 ;
      RECT  78.50 79.00  79.00 80.00 ;
  END
END BWEBM[0]

PIN BWEBM[1]
  DIRECTION INPUT ; USE SIGNAL ;
  PORT
    LAYER M3 ;
      RECT  78.50 78.00  79.00 79.00 ;
  END
END BWEBM[1]

PIN BWEBM[2]
  DIRECTION INPUT ; USE SIGNAL ;
  PORT
    LAYER M3 ;
      RECT  78.50 77.00  79.00 78.00 ;
  END
END BWEBM[2]

PIN BWEBM[3]
  DIRECTION INPUT ; USE SIGNAL ;
  PORT
    LAYER M3 ;
      RECT  78.50 76.00  79.00 77.00 ;
  END
END BWEBM[3]

PIN BWEBM[4]
  DIRECTION INPUT ; USE SIGNAL ;
  PORT
    LAYER M3 ;
      RECT  78.50 75.00  79.00 76.00 ;
  END
END BWEBM[4]

PIN BWEBM[5]
  DIRECTION INPUT ; USE SIGNAL ;
  PORT
    LAYER M3 ;
      RECT  78.50 74.00  79.00 75.00 ;
  END
END BWEBM[5]

PIN BWEBM[6]
  DIRECTION INPUT ; USE SIGNAL ;
  PORT
    LAYER M3 ;
      RECT  78.50 73.00  79.00 74.00 ;
  END
END BWEBM[6]

PIN BWEBM[7]
  DIRECTION INPUT ; USE SIGNAL ;
  PORT
    LAYER M3 ;
      RECT  78.50 72.00  79.00 73.00 ;
  END
END BWEBM[7]

PIN BWEBM[8]
  DIRECTION INPUT ; USE SIGNAL ;
  PORT
    LAYER M3 ;
      RECT  78.50 71.00  79.00 72.00 ;
  END
END BWEBM[8]

PIN BWEBM[9]
  DIRECTION INPUT ; USE SIGNAL ;
  PORT
    LAYER M3 ;
      RECT  78.50 70.00  79.00 71.00 ;
  END
END BWEBM[9]

PIN BWEBM[10]
  DIRECTION INPUT ; USE SIGNAL ;
  PORT
    LAYER M3 ;
      RECT  78.50 69.00  79.00 70.00 ;
  END
END BWEBM[10]

PIN BWEBM[11]
  DIRECTION INPUT ; USE SIGNAL ;
  PORT
    LAYER M3 ;
      RECT  78.50 68.00  79.00 69.00 ;
  END
END BWEBM[11]

PIN BWEBM[12]
  DIRECTION INPUT ; USE SIGNAL ;
  PORT
    LAYER M3 ;
      RECT  78.50 67.00  79.00 68.00 ;
  END
END BWEBM[12]

PIN BWEBM[13]
  DIRECTION INPUT ; USE SIGNAL ;
  PORT
    LAYER M3 ;
      RECT  78.50 66.00  79.00 67.00 ;
  END
END BWEBM[13]

PIN BWEBM[14]
  DIRECTION INPUT ; USE SIGNAL ;
  PORT
    LAYER M3 ;
      RECT  78.50 65.00  79.00 66.00 ;
  END
END BWEBM[14]

PIN BWEBM[15]
  DIRECTION INPUT ; USE SIGNAL ;
  PORT
    LAYER M3 ;
      RECT  78.50 64.00  79.00 65.00 ;
  END
END BWEBM[15]

PIN BWEBM[16]
  DIRECTION INPUT ; USE SIGNAL ;
  PORT
    LAYER M3 ;
      RECT  78.50 63.00  79.00 64.00 ;
  END
END BWEBM[16]

PIN BWEBM[17]
  DIRECTION INPUT ; USE SIGNAL ;
  PORT
    LAYER M3 ;
      RECT  78.50 62.00  79.00 63.00 ;
  END
END BWEBM[17]

PIN BWEBM[18]
  DIRECTION INPUT ; USE SIGNAL ;
  PORT
    LAYER M3 ;
      RECT  78.50 61.00  79.00 62.00 ;
  END
END BWEBM[18]

PIN BWEBM[19]
  DIRECTION INPUT ; USE SIGNAL ;
  PORT
    LAYER M3 ;
      RECT  78.50 60.00  79.00 61.00 ;
  END
END BWEBM[19]

PIN BWEBM[20]
  DIRECTION INPUT ; USE SIGNAL ;
  PORT
    LAYER M3 ;
      RECT  78.50 59.00  79.00 60.00 ;
  END
END BWEBM[20]

PIN BWEBM[21]
  DIRECTION INPUT ; USE SIGNAL ;
  PORT
    LAYER M3 ;
      RECT  78.50 58.00  79.00 59.00 ;
  END
END BWEBM[21]

PIN BWEBM[22]
  DIRECTION INPUT ; USE SIGNAL ;
  PORT
    LAYER M3 ;
      RECT  78.50 57.00  79.00 58.00 ;
  END
END BWEBM[22]

PIN BWEBM[23]
  DIRECTION INPUT ; USE SIGNAL ;
  PORT
    LAYER M3 ;
      RECT  78.50 56.00  79.00 57.00 ;
  END
END BWEBM[23]

PIN BWEBM[24]
  DIRECTION INPUT ; USE SIGNAL ;
  PORT
    LAYER M3 ;
      RECT  78.50 55.00  79.00 56.00 ;
  END
END BWEBM[24]

PIN BWEBM[25]
  DIRECTION INPUT ; USE SIGNAL ;
  PORT
    LAYER M3 ;
      RECT  78.50 54.00  79.00 55.00 ;
  END
END BWEBM[25]

PIN BWEBM[26]
  DIRECTION INPUT ; USE SIGNAL ;
  PORT
    LAYER M3 ;
      RECT  78.50 53.00  79.00 54.00 ;
  END
END BWEBM[26]

PIN BWEBM[27]
  DIRECTION INPUT ; USE SIGNAL ;
  PORT
    LAYER M3 ;
      RECT  78.50 52.00  79.00 53.00 ;
  END
END BWEBM[27]

PIN BWEBM[28]
  DIRECTION INPUT ; USE SIGNAL ;
  PORT
    LAYER M3 ;
      RECT  78.50 51.00  79.00 52.00 ;
  END
END BWEBM[28]

PIN BWEBM[29]
  DIRECTION INPUT ; USE SIGNAL ;
  PORT
    LAYER M3 ;
      RECT  78.50 50.00  79.00 51.00 ;
  END
END BWEBM[29]

PIN BWEBM[30]
  DIRECTION INPUT ; USE SIGNAL ;
  PORT
    LAYER M3 ;
      RECT  78.50 49.00  79.00 50.00 ;
  END
END BWEBM[30]

PIN BWEBM[31]
  DIRECTION INPUT ; USE SIGNAL ;
  PORT
    LAYER M3 ;
      RECT  78.50 48.00  79.00 49.00 ;
  END
END BWEBM[31]

PIN BWEBM[32]
  DIRECTION INPUT ; USE SIGNAL ;
  PORT
    LAYER M3 ;
      RECT  78.50 47.00  79.00 48.00 ;
  END
END BWEBM[32]

PIN BWEBM[33]
  DIRECTION INPUT ; USE SIGNAL ;
  PORT
    LAYER M3 ;
      RECT  78.50 46.00  79.00 47.00 ;
  END
END BWEBM[33]

PIN BWEBM[34]
  DIRECTION INPUT ; USE SIGNAL ;
  PORT
    LAYER M3 ;
      RECT  78.50 45.00  79.00 46.00 ;
  END
END BWEBM[34]

PIN BWEBM[35]
  DIRECTION INPUT ; USE SIGNAL ;
  PORT
    LAYER M3 ;
      RECT  78.50 44.00  79.00 45.00 ;
  END
END BWEBM[35]

PIN BWEBM[36]
  DIRECTION INPUT ; USE SIGNAL ;
  PORT
    LAYER M3 ;
      RECT  78.50 43.00  79.00 44.00 ;
  END
END BWEBM[36]

PIN BWEBM[37]
  DIRECTION INPUT ; USE SIGNAL ;
  PORT
    LAYER M3 ;
      RECT  78.50 42.00  79.00 43.00 ;
  END
END BWEBM[37]

PIN BWEBM[38]
  DIRECTION INPUT ; USE SIGNAL ;
  PORT
    LAYER M3 ;
      RECT  78.50 41.00  79.00 42.00 ;
  END
END BWEBM[38]

PIN BWEBM[39]
  DIRECTION INPUT ; USE SIGNAL ;
  PORT
    LAYER M3 ;
      RECT  78.50 40.00  79.00 41.00 ;
  END
END BWEBM[39]

PIN BWEBM[40]
  DIRECTION INPUT ; USE SIGNAL ;
  PORT
    LAYER M3 ;
      RECT  78.50 39.00  79.00 40.00 ;
  END
END BWEBM[40]

PIN BWEBM[41]
  DIRECTION INPUT ; USE SIGNAL ;
  PORT
    LAYER M3 ;
      RECT  78.50 38.00  79.00 39.00 ;
  END
END BWEBM[41]

PIN BWEBM[42]
  DIRECTION INPUT ; USE SIGNAL ;
  PORT
    LAYER M3 ;
      RECT  78.50 37.00  79.00 38.00 ;
  END
END BWEBM[42]

PIN BWEBM[43]
  DIRECTION INPUT ; USE SIGNAL ;
  PORT
    LAYER M3 ;
      RECT  78.50 36.00  79.00 37.00 ;
  END
END BWEBM[43]

PIN BWEBM[44]
  DIRECTION INPUT ; USE SIGNAL ;
  PORT
    LAYER M3 ;
      RECT  78.50 35.00  79.00 36.00 ;
  END
END BWEBM[44]

PIN BWEBM[45]
  DIRECTION INPUT ; USE SIGNAL ;
  PORT
    LAYER M3 ;
      RECT  78.50 34.00  79.00 35.00 ;
  END
END BWEBM[45]

PIN BWEBM[46]
  DIRECTION INPUT ; USE SIGNAL ;
  PORT
    LAYER M3 ;
      RECT  78.50 33.00  79.00 34.00 ;
  END
END BWEBM[46]

PIN BWEBM[47]
  DIRECTION INPUT ; USE SIGNAL ;
  PORT
    LAYER M3 ;
      RECT  78.50 32.00  79.00 33.00 ;
  END
END BWEBM[47]

PIN BWEBM[48]
  DIRECTION INPUT ; USE SIGNAL ;
  PORT
    LAYER M3 ;
      RECT  78.50 31.00  79.00 32.00 ;
  END
END BWEBM[48]

PIN BWEBM[49]
  DIRECTION INPUT ; USE SIGNAL ;
  PORT
    LAYER M3 ;
      RECT  78.50 30.00  79.00 31.00 ;
  END
END BWEBM[49]

PIN BWEBM[50]
  DIRECTION INPUT ; USE SIGNAL ;
  PORT
    LAYER M3 ;
      RECT  78.50 29.00  79.00 30.00 ;
  END
END BWEBM[50]

PIN BWEBM[51]
  DIRECTION INPUT ; USE SIGNAL ;
  PORT
    LAYER M3 ;
      RECT  78.50 28.00  79.00 29.00 ;
  END
END BWEBM[51]

PIN BWEBM[52]
  DIRECTION INPUT ; USE SIGNAL ;
  PORT
    LAYER M3 ;
      RECT  78.50 27.00  79.00 28.00 ;
  END
END BWEBM[52]

PIN BWEBM[53]
  DIRECTION INPUT ; USE SIGNAL ;
  PORT
    LAYER M3 ;
      RECT  78.50 26.00  79.00 27.00 ;
  END
END BWEBM[53]

PIN BWEBM[54]
  DIRECTION INPUT ; USE SIGNAL ;
  PORT
    LAYER M3 ;
      RECT  78.50 25.00  79.00 26.00 ;
  END
END BWEBM[54]

PIN BWEBM[55]
  DIRECTION INPUT ; USE SIGNAL ;
  PORT
    LAYER M3 ;
      RECT  78.50 24.00  79.00 25.00 ;
  END
END BWEBM[55]

PIN BWEBM[56]
  DIRECTION INPUT ; USE SIGNAL ;
  PORT
    LAYER M3 ;
      RECT  78.50 23.00  79.00 24.00 ;
  END
END BWEBM[56]

PIN BWEBM[57]
  DIRECTION INPUT ; USE SIGNAL ;
  PORT
    LAYER M3 ;
      RECT  78.50 22.00  79.00 23.00 ;
  END
END BWEBM[57]

PIN BWEBM[58]
  DIRECTION INPUT ; USE SIGNAL ;
  PORT
    LAYER M3 ;
      RECT  78.50 21.00  79.00 22.00 ;
  END
END BWEBM[58]

PIN BWEBM[59]
  DIRECTION INPUT ; USE SIGNAL ;
  PORT
    LAYER M3 ;
      RECT  78.50 20.00  79.00 21.00 ;
  END
END BWEBM[59]

PIN BWEBM[60]
  DIRECTION INPUT ; USE SIGNAL ;
  PORT
    LAYER M3 ;
      RECT  78.50 19.00  79.00 20.00 ;
  END
END BWEBM[60]

PIN BWEBM[61]
  DIRECTION INPUT ; USE SIGNAL ;
  PORT
    LAYER M3 ;
      RECT  78.50 18.00  79.00 19.00 ;
  END
END BWEBM[61]

PIN BWEBM[62]
  DIRECTION INPUT ; USE SIGNAL ;
  PORT
    LAYER M3 ;
      RECT  78.50 17.00  79.00 18.00 ;
  END
END BWEBM[62]

PIN BWEBM[63]
  DIRECTION INPUT ; USE SIGNAL ;
  PORT
    LAYER M3 ;
      RECT  78.50 16.00  79.00 17.00 ;
  END
END BWEBM[63]

END TS6N40LPA24X64M2F
